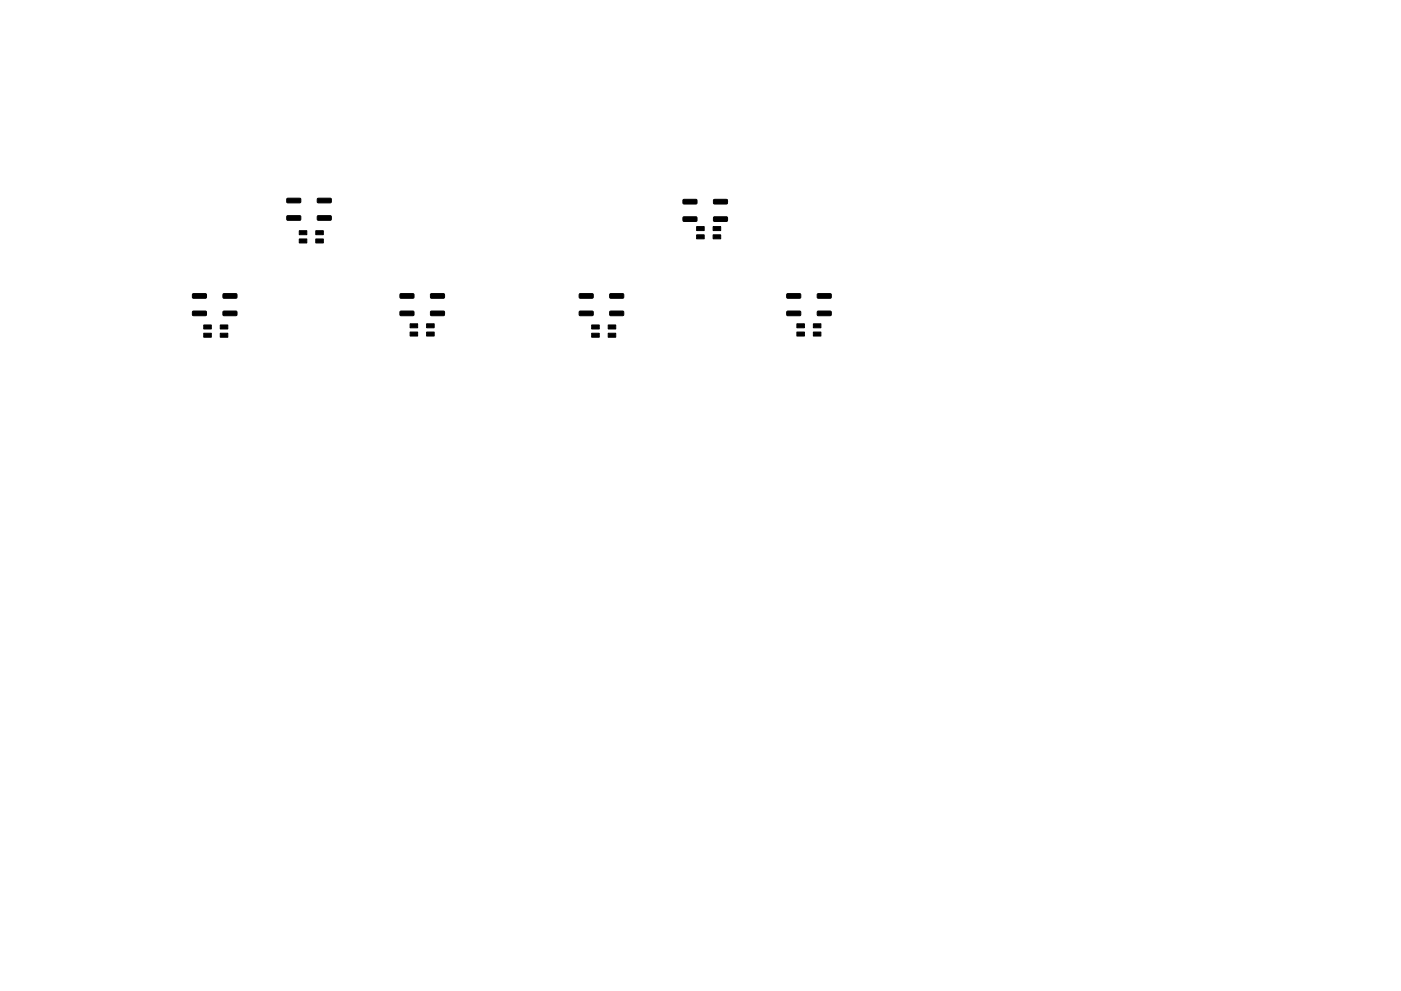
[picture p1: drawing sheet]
<svg xmlns="http://www.w3.org/2000/svg" width="297mm" height="210mm" viewBox="0 0 297 210" stroke-linecap="round" stroke-linejoin="round" font-family="sans-serif">
<g fill="#000" stroke="#000" stroke-width=".21">
<path d="M63.4 50.7h1.6v.8h-1.6zM63.4 48.9h1.6v.9h-1.6zM60.9 42.1h2.7l.2 .1v.7l-.2 .1h-2.6l-.2-.2zM60.9 45.8h2.7l.2 .1v.7l-.2 .1h-2.6l-.2-.2zM67 50.7h1.6v.8h-1.6zM67 48.9h1.6v.9h-1.6zM67.3 42.1h2.8l.2 .1v.6l-.3 .2h-2.6l-.1-.2zM67.3 45.8h2.8l.2 .1v.6l-.3 .2h-2.5l-.2-.2zM144.9 46.1l2.7-.1 .2 .2v.6l-.2 .2h-2.6l-.2-.2zM144.9 42.4l2.7-.1 .2 .2v.6l-.2 .2h-2.6l-.2-.2zM147.7 48.1h1.6v.8h-1.6zM147.7 49.8h1.6v.9h-1.6z"/>
<path d="M151.2 48.1h1.6v.8h-1.6zM151.2 49.8h1.6v.9h-1.6zM151.3 46.1l2.8-.1 .2 .2-.1 .6-.2 .2h-2.5l-.2-.2zM151.3 42.4l2.8-.1 .2 .2-.1 .6-.2 .2h-2.5l-.2-.2zM40.9 62.4l2.7-.1 .2 .2v.6l-.2 .2h-2.6l-.2-.2zM40.9 66.1l2.7-.1 .2 .2v.6l-.2 .2h-2.6l-.2-.2zM43.2 70.7h1.6v.8h-1.6zM43.2 68.9h1.6v.9h-1.6zM46.7 70.7h1.6v.8h-1.6zM46.7 68.9h1.6v.9h-1.6zM47.3 62.4l2.8-.1 .2 .2-.1 .6-.2 .2h-2.6l-.1-.2zM47.3 66.1l2.8-.1 .2 .2-.1 .6-.2 .2h-2.6l-.1-.2z"/>
<path d="M84.9 62.4l2.7-.1 .2 .2v.6l-.2 .2h-2.6l-.2-.2zM84.9 66.1l2.7-.1 .2 .2v.6l-.2 .2h-2.6l-.2-.2zM87 68.7h1.5v.8h-1.5zM87 70.4h1.5v.9h-1.5zM90.4 68.7h1.7v.8h-1.7zM90.4 70.4h1.7v.9h-1.7zM91.3 62.4l2.8-.1 .2 .2v.6l-.3 .2h-2.6l-.1-.2zM91.3 66.1l2.8-.1 .2 .2v.6l-.3 .2h-2.6l-.1-.2zM122.9 66.1l2.7-.1 .2 .2v.6l-.2 .2h-2.6l-.2-.2zM122.9 62.4l2.7-.1 .2 .2v.6l-.2 .2h-2.6l-.2-.2zM125.5 70.7h1.6v.8h-1.6zM125.5 68.9h1.6v.9h-1.6z"/>
<path d="M128.9 70.7h1.6v.8h-1.6zM128.9 68.9h1.6v.9h-1.6zM129.3 66.1l2.8-.1 .2 .2-.1 .6-.2 .2h-2.6l-.1-.2zM129.3 62.4l2.8-.1 .2 .2-.1 .6-.2 .2h-2.6l-.1-.2zM166.9 66.1l2.7-.1 .2 .2v.6l-.2 .2h-2.6l-.2-.2zM166.9 62.4l2.7-.1 .2 .2v.6l-.2 .2h-2.6l-.2-.2zM168.9 68.7h1.7v.8h-1.7zM168.9 70.4h1.7v.9h-1.7zM172.5 68.7h1.5v.8h-1.5zM172.5 70.4h1.5v.9h-1.5zM173.3 66.1l2.8-.1 .2 .2-.1 .6-.2 .2h-2.6l-.1-.2zM173.3 62.4l2.8-.1 .2 .2-.1 .6-.2 .2h-2.6l-.1-.2z"/>
</g>
</svg>
